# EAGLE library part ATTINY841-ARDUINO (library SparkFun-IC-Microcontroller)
ATtiny841

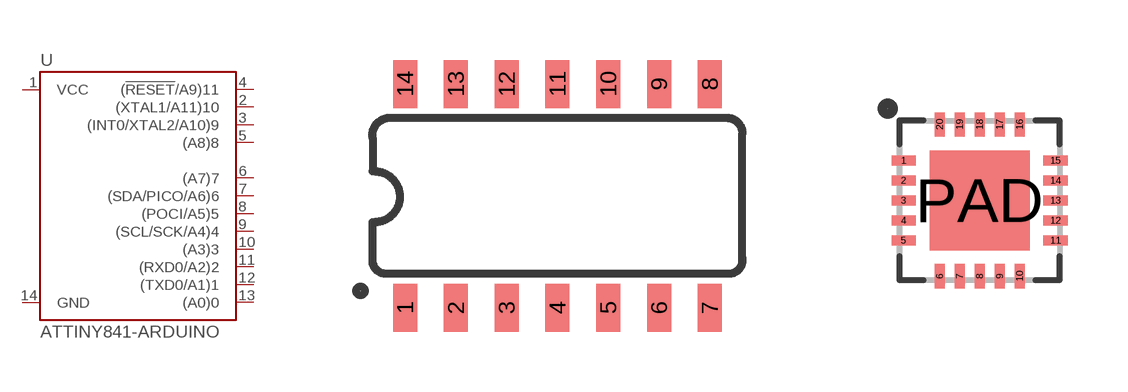
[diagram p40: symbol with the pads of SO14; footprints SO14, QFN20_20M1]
Designator prefix U

## ATTINY841-ARDUINO (PROD_ID: IC-14692; VALUE: ATtiny841)  [SO14]
1  VCC  pwr
2  (XTAL1/A11)10
3  (INT0/XTAL2/A10)9
4  (!RESET!/A9)11
5  (A8)8
6  (A7)7
7  (SDA/PICO/A6)6
8  (POCI/A5)5
9  (SCL/SCK/A4)4
10  (A3)3
11  (RXD0/A2)2
12  (TXD0/A1)1
13  (A0)0
14  GND  pwr

## ATTINY841-ARDUINO_QFN20M1 (DIGIKEY_PART: ATTINY841-MU-ND; PROD_ID: IC-16067)  [QFN20_20M1]
1  (SCL/SCK/A4)4
2  (A3)3
3  (RXD0/A2)2
4  (TXD0/A1)1
5  (A0)0
8  GND  pwr
9  VCC  pwr
11  (XTAL1/A11)10
12  (INT0/XTAL2/A10)9
13  (!RESET!/A9)11
14  (A8)8
15  (A7)7
16  (SDA/PICO/A6)6
20  (POCI/A5)5
PAD  GND  pwr

## Footprint SO14 (pad centres in mm)
SOIC, 0.15 inch width
smd 0.6 x 1.2: 1 -3.81,-2.8; 2 -2.54,-2.8; 3 -1.27,-2.8; 4 0,-2.8; 5 1.27,-2.8; 6 2.54,-2.8; 7 3.81,-2.8; 8 3.81,2.8; 9 2.54,2.8; 10 1.27,2.8; 11 0,2.8; 12 -1.27,2.8; 13 -2.54,2.8; 14 -3.81,2.8

## Footprint QFN20_20M1 (pad centres in mm)
smd 0.6 x 0.25: 1 -1.9,1; 2 -1.9,0.5; 3 -1.9,0; 4 -1.9,-0.5; 5 -1.9,-1; 11 1.9,-1; 12 1.9,-0.5; 13 1.9,0; 14 1.9,0.5; 15 1.9,1
smd 0.25 x 0.6: 6 -1,-1.9; 7 -0.5,-1.9; 8 0,-1.9; 9 0.5,-1.9; 10 1,-1.9; 16 1,1.9; 17 0.5,1.9; 18 0,1.9; 19 -0.5,1.9; 20 -1,1.9
smd 2.5 x 2.5: PAD 0,0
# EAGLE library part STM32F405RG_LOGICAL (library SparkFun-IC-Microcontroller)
STM32F405RGT6 ARM DSP Chip used on the WAV Trigger board. IC MCU 32BIT 1MB FLASH 64LQFP Datasheet SparkFun Products WAV Trigger (WIG-13660)

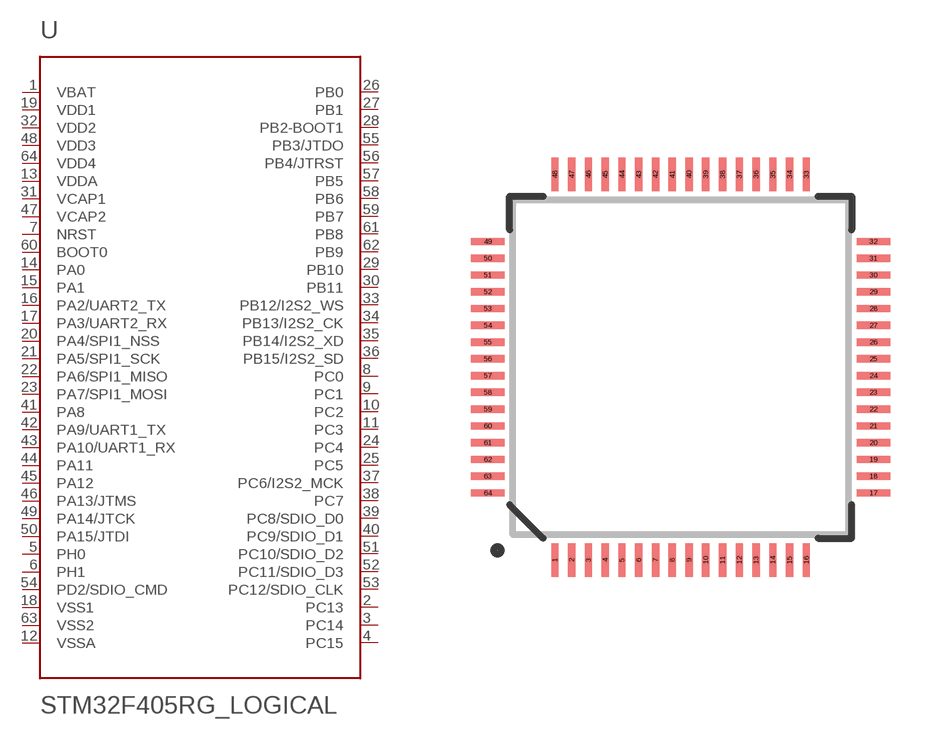
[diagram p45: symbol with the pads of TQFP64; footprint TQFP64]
Designator prefix -

## STM32F405RG_LOGICAL (PROD_ID: IC-11709; VALUE: STM32F405RGT6)  [TQFP64]
1  VBAT
2  PC13
3  PC14
4  PC15
5  PH0
6  PH1
7  NRST
8  PC0
9  PC1
10  PC2
11  PC3
12  VSSA
13  VDDA
14  PA0
15  PA1
16  PA2/UART2_TX
17  PA3/UART2_RX
18  VSS1
19  VDD1
20  PA4/SPI1_NSS
21  PA5/SPI1_SCK
22  PA6/SPI1_MISO
23  PA7/SPI1_MOSI
24  PC4
25  PC5
26  PB0
27  PB1
28  PB2-BOOT1
29  PB10
30  PB11
31  VCAP1
32  VDD2
33  PB12/I2S2_WS
34  PB13/I2S2_CK
35  PB14/I2S2_XD
36  PB15/I2S2_SD
37  PC6/I2S2_MCK
38  PC7
39  PC8/SDIO_D0
40  PC9/SDIO_D1
41  PA8
42  PA9/UART1_TX
43  PA10/UART1_RX
44  PA11
45  PA12
46  PA13/JTMS
47  VCAP2
48  VDD3
49  PA14/JTCK
50  PA15/JTDI
51  PC10/SDIO_D2
52  PC11/SDIO_D3
53  PC12/SDIO_CLK
54  PD2/SDIO_CMD
55  PB3/JTDO
56  PB4/JTRST
57  PB5
58  PB6
59  PB7
60  BOOT0
61  PB8
62  PB9
63  VSS2
64  VDD4

## Footprint TQFP64 (pad centres in mm)
64-Lead TQFP Plastic Thin Quad Flatpack - 10x10x1mm Body, 2mmFP
smd 0.22 x 1: 1 -3.75,-5.75; 2 -3.25,-5.75; 3 -2.75,-5.75; 4 -2.25,-5.75; 5 -1.75,-5.75; 6 -1.25,-5.75; 7 -0.75,-5.75; 8 -0.25,-5.75; 9 0.25,-5.75; 10 0.75,-5.75; 11 1.25,-5.75; 12 1.75,-5.75; 13 2.25,-5.75; 14 2.75,-5.75; 15 3.25,-5.75; 16 3.75,-5.75; 33 3.75,5.75; 34 3.25,5.75; 35 2.75,5.75; 36 2.25,5.75; 37 1.75,5.75; 38 1.25,5.75; 39 0.75,5.75; 40 0.25,5.75; 41 -0.25,5.75; 42 -0.75,5.75; 43 -1.25,5.75; 44 -1.75,5.75; 45 -2.25,5.75; 46 -2.75,5.75; 47 -3.25,5.75; 48 -3.75,5.75
smd 1 x 0.22: 17 5.75,-3.75; 18 5.75,-3.25; 19 5.75,-2.75; 20 5.75,-2.25; 21 5.75,-1.75; 22 5.75,-1.25; 23 5.75,-0.75; 24 5.75,-0.25; 25 5.75,0.25; 26 5.75,0.75; 27 5.75,1.25; 28 5.75,1.75; 29 5.75,2.25; 30 5.75,2.75; 31 5.75,3.25; 32 5.75,3.75; 49 -5.75,3.75; 50 -5.75,3.25; 51 -5.75,2.75; 52 -5.75,2.25; 53 -5.75,1.75; 54 -5.75,1.25; 55 -5.75,0.75; 56 -5.75,0.25; 57 -5.75,-0.25; 58 -5.75,-0.75; 59 -5.75,-1.25; 60 -5.75,-1.75; 61 -5.75,-2.25; 62 -5.75,-2.75; 63 -5.75,-3.25; 64 -5.75,-3.75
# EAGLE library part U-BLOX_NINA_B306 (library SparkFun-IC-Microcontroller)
u-blox NINA B306 BLE Module A low energy bluetooth controller, using the nRF52840. Datasheet

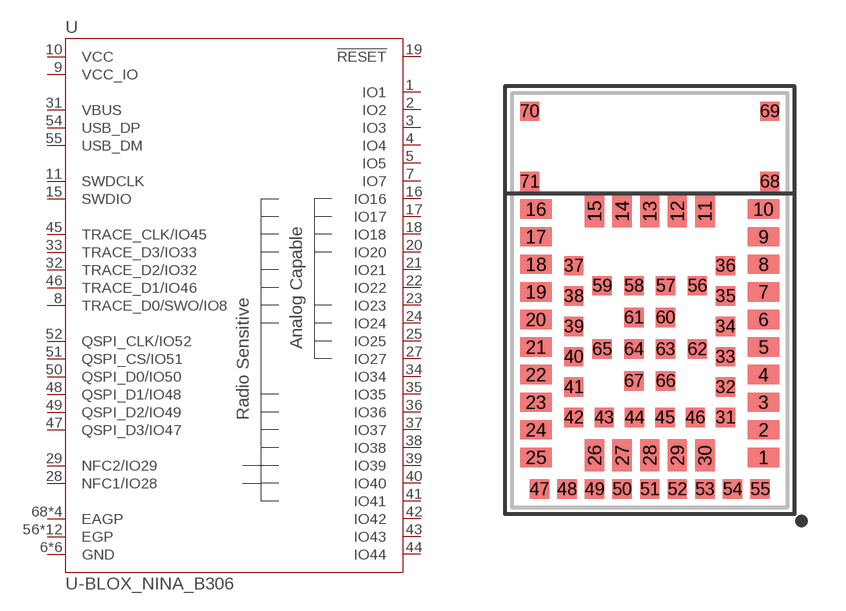
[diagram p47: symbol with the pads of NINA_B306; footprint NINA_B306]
Designator prefix U

## U-BLOX_NINA_B306 (PROD_ID: IC-16760)  [NINA_B306]
1  IO1
2  IO2
3  IO3
4  IO4
5  IO5
6  GND  pwr
7  IO7
8  TRACE_D0/SWO/IO8
9  VCC_IO  pwr
10  VCC  pwr
11  SWDCLK
12  GND  pwr
14  GND  pwr
15  SWDIO
16  IO16
17  IO17
18  IO18
19  !RESET!  in
20  IO20
21  IO21
22  IO22
23  IO23
24  IO24
25  IO25
26  GND  pwr
27  IO27
28  NFC1/IO28
29  NFC2/IO29
30  GND  pwr
31  VBUS  pwr
32  TRACE_D2/IO32
33  TRACE_D3/IO33
34  IO34
35  IO35
36  IO36
37  IO37
38  IO38
39  IO39
40  IO40
41  IO41
42  IO42
43  IO43
44  IO44
45  TRACE_CLK/IO45
46  TRACE_D1/IO46
47  QSPI_D3/IO47
48  QSPI_D1/IO48
49  QSPI_D2/IO49
50  QSPI_D0/IO50
51  QSPI_CS/IO51
52  QSPI_CLK/IO52
53  GND  pwr
54  USB_DP
55  USB_DM
56  EGP  pwr
57  EGP  pwr
58  EGP  pwr
59  EGP  pwr
60  EGP  pwr
61  EGP  pwr
62  EGP  pwr
63  EGP  pwr
64  EGP  pwr
65  EGP  pwr
66  EGP  pwr
67  EGP  pwr
68  EAGP  pwr
69  EAGP  pwr
70  EAGP  pwr
71  EAGP  pwr

## Footprint NINA_B306 (pad centres in mm)
NINA-B3x6 Package Pin Count: 71 Dimensions: 15.0 x 10.0 mm Pitch: 1.0 mm Datasheet referenced for footprint
smd 1.15 x 0.7: 1 4.125,-5.7; 2 4.125,-4.7; 3 4.125,-3.7; 4 4.125,-2.7; 5 4.125,-1.7; 6 4.125,-0.7; 7 4.125,0.3; 8 4.125,1.3; 9 4.125,2.3; 10 4.125,3.3; 16 -4.125,3.3; 17 -4.125,2.3; 18 -4.125,1.3; 19 -4.125,0.3; 20 -4.125,-0.7; 21 -4.125,-1.7; 22 -4.125,-2.7; 23 -4.125,-3.7; 24 -4.125,-4.7; 25 -4.125,-5.7
smd 0.7 x 1.15: 11 2,3.225; 12 1,3.225; 13 0,3.225; 14 -1,3.225; 15 -2,3.225; 26 -2,-5.625; 27 -1,-5.625; 28 0,-5.625; 29 1,-5.625; 30 2,-5.625
smd 0.7 x 0.7: 31 2.75,-4.25; 32 2.75,-3.15; 33 2.75,-2.05; 34 2.75,-0.95; 35 2.75,0.15; 36 2.75,1.25; 37 -2.75,1.25; 38 -2.75,0.15; 39 -2.75,-0.95; 40 -2.75,-2.05; 41 -2.75,-3.15; 42 -2.75,-4.25; 43 -1.65,-4.25; 44 -0.55,-4.25; 45 0.55,-4.25; 46 1.65,-4.25; 47 -4,-6.85; 48 -3,-6.85; 49 -2,-6.85; 50 -1,-6.85; 51 0,-6.85; 52 1,-6.85; 53 2,-6.85; 54 3,-6.85; 55 4,-6.85; 56 1.725,0.525; 57 0.575,0.525; 58 -0.575,0.525; 59 -1.725,0.525; 60 0.575,-0.625; 61 -0.575,-0.625; 62 1.725,-1.775; 63 0.575,-1.775; 64 -0.575,-1.775; 65 -1.725,-1.775; 66 0.575,-2.925; 67 -0.575,-2.925; 68 4.35,4.3; 69 4.35,6.85; 70 -4.35,6.85; 71 -4.35,4.3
